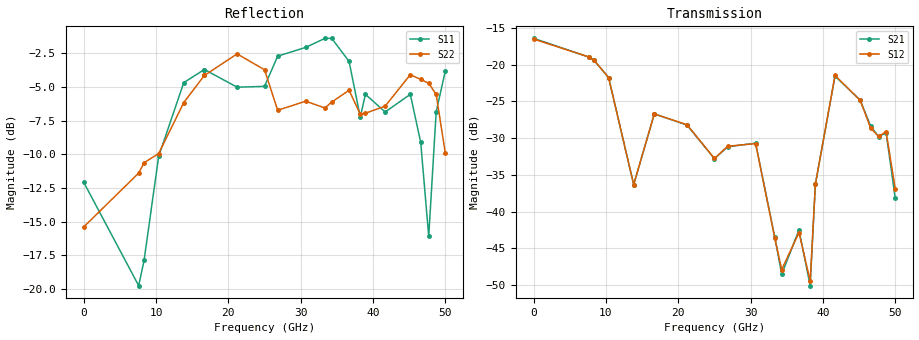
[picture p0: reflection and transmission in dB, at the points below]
!Keysight Technologies,N5245B,MY58422270,A.16.20.02
!Date: Thursday, March 05, 2026 01:15:24
!Correction: S11(C  2-Port  )
!S21(C  2-Port  )
!S12(C  2-Port  )
!S22(C  2-Port  )
!S2P File: Measurements: S11, S21, S12, S22:
# Hz S  dB  R 50
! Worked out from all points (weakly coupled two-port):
!   3201 points, 10 MHz to 50 GHz, reference 50 ohm
!   highest |S21| = -16.44 dB at 10 MHz (marker M1); lowest = -50.1 dB at 38.24 GHz (marker M2)
!   lowest |S11| = -19.7 dB at 7.602 GHz (marker M3), VSWR 1.23, Z = 40.7 - j1.26 ohm
!   |S11| at or under -10 dB: start of sweep to 10.42 GHz; 46.74 GHz to 48.25 GHz (1.518 GHz wide, 3.2 % of centre)
!   |S22| runs from -19.5 to -2.5 dB; largest |S21 - S12| = 0.0072
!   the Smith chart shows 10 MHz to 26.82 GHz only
!   S11 on the Smith chart (normalised r, x): 10 MHz: 1.66, -0.03; 10.37 GHz: 0.54, +0.14; 13.84 GHz: 1.14, +1.53; 16.69 GHz: 1.25, -1.91; 21.21 GHz: 0.32, -0.36; 26.82 GHz: 0.17, +0.34
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1e7  -12.08 -1.9  -16.44 4.2  -16.54 3.6  -15.38 40.1
7.602231e9  -19.74 -171.5  -18.97 40.3  -18.96 40.5  -11.39 -163.5
8.352081e9  -17.85 -162.6  -19.42 7.0  -19.40 7.0  -10.62 179.4
1.03673e10  -10.14 158.0  -21.77 -81.5  -21.77 -81.6  -9.94 115.8
1.383536e10  -4.68 49.3  -36.34 -160.7  -36.32 -160.0  -6.16 -55.3
1.667854e10  -3.71 -41.7  -26.75 158.7  -26.74 158.9  -4.15 -144.5
1.669416e10  -3.71 -42.1  -26.72 158.1  -26.72 158.3  -4.15 -144.8
2.120888e10  -5.02 -137.1  -28.23 19.4  -28.19 19.4  -2.55 135.6
2.5005e10  -4.96 174.7  -32.81 -66.7  -32.78 -67.3  -3.73 70.5
2.681714e10  -2.72 141.7  -31.19 -105.9  -31.12 -107.1  -6.73 38.5
3.069136e10  -2.07 78.2  -30.70 119.5  -30.75 118.5  -6.06 -55.9
3.334708e10  -1.40 35.7  -43.48 -1.7  -43.63 -7.5  -6.56 -133.0
3.430002e10  -1.40 19.1  -48.54 -94.6  -47.88 -97.8  -6.12 -154.1
3.669016e10  -3.11 -31.2  -42.49 104.2  -42.86 107.5  -5.25 158.8
3.823673e10  -7.23 -21.8  -50.08 -105.7  -49.45 95.4  -7.02 133.8
3.895533e10  -5.55 -30.2  -36.28 96.0  -36.29 100.3  -6.95 136.8
4.167354e10  -6.86 -55.2  -21.57 -56.5  -21.48 -56.9  -6.43 110.2
4.515722e10  -5.55 -102.4  -24.86 83.5  -24.88 82.5  -4.09 73.6
4.659443e10  -9.11 -153.4  -28.36 31.4  -28.66 29.9  -4.45 53.9
4.770358e10  -16.08 71.9  -29.83 -14.8  -29.78 -15.2  -4.73 41.8
4.873463e10  -6.84 -25.9  -29.26 -89.7  -29.13 -88.2  -5.56 21.0
5e10  -3.81 -72.6  -38.22 -126.0  -36.90 -125.8  -9.92 8.2
